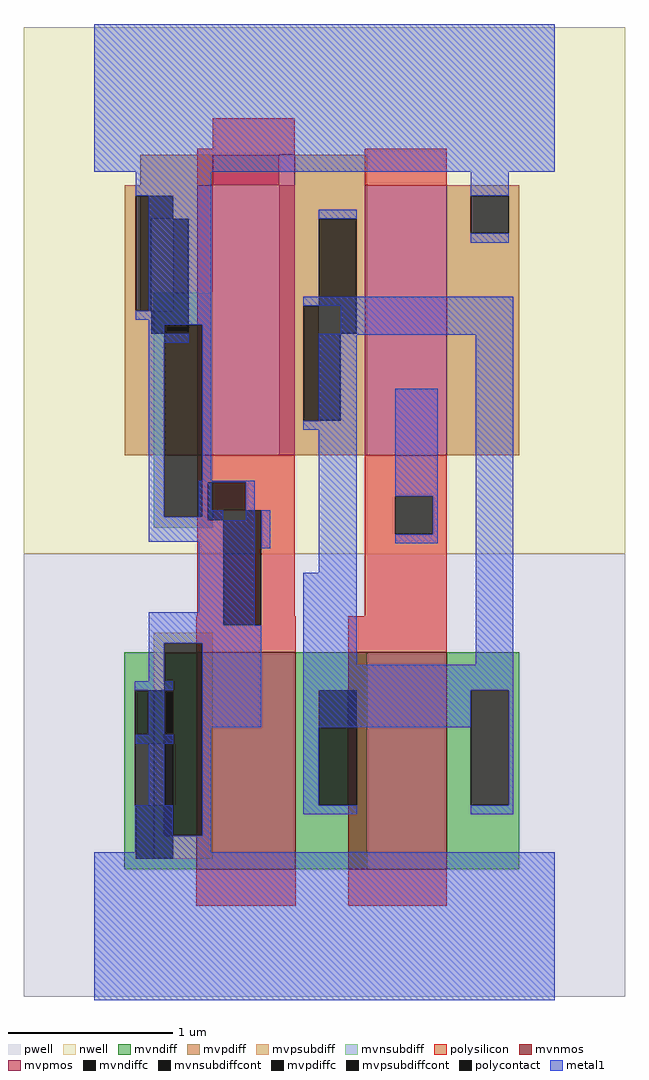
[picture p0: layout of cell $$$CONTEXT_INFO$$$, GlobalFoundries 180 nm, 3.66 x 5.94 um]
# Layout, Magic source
magic
tech gf180mcuD
magscale 1 10
use gf180mcu_fd_sc_mcu9t5v0__filltie  gf180mcu_fd_sc_mcu9t5v0__filltie_0
transform 1 0 0 0 1 0
box -86 -90 310 1098
use gf180mcu_fd_sc_mcu9t5v0__inv_1  gf180mcu_fd_sc_mcu9t5v0__inv_1_0
transform 1 0 0 0 1 0
box -86 -90 534 1098
use gf180mcu_fd_sc_mcu9t5v0__nand2_1  gf180mcu_fd_sc_mcu9t5v0__nand2_1_0
transform 1 0 0 0 1 0
box -86 -90 646 1098
<< end >>

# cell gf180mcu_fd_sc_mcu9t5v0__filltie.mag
magic
tech gf180mcuD
magscale 1 10
<< nwell >>
rect -86 453 310 1094
<< pwell >>
rect -86 -86 310 453
<< mvpsubdiff >>
rect 72 344 144 357
rect 72 110 85 344
rect 131 110 144 344
rect 72 82 144 110
<< mvnsubdiff >>
rect 72 732 144 771
rect 72 498 85 732
rect 131 498 144 732
rect 72 485 144 498
<< mvpsubdiffcont >>
rect 85 110 131 344
<< mvnsubdiffcont >>
rect 85 498 131 732
<< metal1 >>
rect 0 918 224 1098
rect 66 732 142 918
rect 66 498 85 732
rect 131 498 142 732
rect 66 468 142 498
rect 66 344 142 382
rect 66 110 85 344
rect 131 110 142 344
rect 66 90 142 110
rect 0 -90 224 90
<< labels >>
flabel metal1 s 112 -90 112 -90 0 FreeSans 200 0 0 0 VSS
port 1 nsew
flabel metal1 s 112 1098 112 1098 0 FreeSans 200 0 0 0 VDD
port 2 nsew
<< properties >>
string FIXED_BBOX 0 0 224 1008
<< end >>

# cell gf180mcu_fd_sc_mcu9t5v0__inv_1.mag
magic
tech gf180mcuD
magscale 1 10
<< nwell >>
rect -86 453 534 1094
<< pwell >>
rect -86 -86 534 453
<< mvnmos >>
rect 124 69 244 333
<< mvpmos >>
rect 144 573 244 939
<< mvndiff >>
rect 36 287 124 333
rect 36 147 49 287
rect 95 147 124 287
rect 36 69 124 147
rect 244 287 332 333
rect 244 147 273 287
rect 319 147 332 287
rect 244 69 332 147
<< mvpdiff >>
rect 56 861 144 939
rect 56 721 69 861
rect 115 721 144 861
rect 56 573 144 721
rect 244 861 332 939
rect 244 721 273 861
rect 319 721 332 861
rect 244 573 332 721
<< mvndiffc >>
rect 49 147 95 287
rect 273 147 319 287
<< mvpdiffc >>
rect 69 721 115 861
rect 273 721 319 861
<< polysilicon >>
rect 144 939 244 983
rect 144 506 244 573
rect 144 377 157 506
rect 124 366 157 377
rect 203 366 244 506
rect 124 333 244 366
rect 124 25 244 69
<< polycontact >>
rect 157 366 203 506
<< metal1 >>
rect 0 918 448 1098
rect 69 861 115 918
rect 69 710 115 721
rect 273 861 319 872
rect 142 366 157 506
rect 203 460 214 506
rect 273 430 319 721
rect 49 287 95 298
rect 142 242 203 366
rect 254 287 319 430
rect 49 90 95 147
rect 254 147 273 287
rect 254 136 319 147
rect 0 -90 448 90
<< labels >>
flabel metal1 s 168 392 168 392 0 FreeSans 200 0 0 0 I
port 1 nsew
flabel metal1 s 224 1098 224 1098 0 FreeSans 200 0 0 0 VDD
port 2 nsew
flabel metal1 s 224 -90 224 -90 0 FreeSans 200 0 0 0 VSS
port 3 nsew
flabel metal1 s 280 392 280 392 0 FreeSans 200 0 0 0 ZN
port 4 nsew
flabel nwell s 69 784 69 784 0 FreeSans 400 0 0 0 VNW
port 5 nsew
flabel pwell s 68 -17 68 -17 0 FreeSans 400 0 0 0 VPW
port 6 nsew
<< properties >>
string FIXED_BBOX 0 0 448 1008
<< end >>

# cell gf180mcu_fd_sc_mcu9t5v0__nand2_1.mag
magic
tech gf180mcuD
magscale 1 10
<< nwell >>
rect -86 453 646 1094
<< pwell >>
rect -86 -86 646 453
<< mvnmos >>
rect 125 69 245 333
rect 309 69 429 333
<< mvpmos >>
rect 125 573 225 902
rect 329 573 429 902
<< mvndiff >>
rect 37 222 125 333
rect 37 82 50 222
rect 96 82 125 222
rect 37 69 125 82
rect 245 69 309 333
rect 429 287 517 333
rect 429 147 458 287
rect 504 147 517 287
rect 429 69 517 147
<< mvpdiff >>
rect 37 889 125 902
rect 37 749 50 889
rect 96 749 125 889
rect 37 573 125 749
rect 225 755 329 902
rect 225 615 254 755
rect 300 615 329 755
rect 225 573 329 615
rect 429 889 517 902
rect 429 843 458 889
rect 504 843 517 889
rect 429 573 517 843
<< mvndiffc >>
rect 50 82 96 222
rect 458 147 504 287
<< mvpdiffc >>
rect 50 749 96 889
rect 254 615 300 755
rect 458 843 504 889
<< polysilicon >>
rect 125 902 225 946
rect 329 902 429 946
rect 125 540 225 573
rect 125 494 138 540
rect 184 494 225 540
rect 125 377 225 494
rect 329 523 429 573
rect 329 477 366 523
rect 412 477 429 523
rect 329 377 429 477
rect 125 333 245 377
rect 309 333 429 377
rect 125 25 245 69
rect 309 25 429 69
<< polycontact >>
rect 138 494 184 540
rect 366 477 412 523
<< metal1 >>
rect 0 918 560 1098
rect 50 889 96 918
rect 458 889 504 918
rect 458 832 504 843
rect 50 738 96 749
rect 254 755 510 766
rect 300 720 510 755
rect 300 615 306 720
rect 254 604 306 615
rect 127 540 195 542
rect 127 494 138 540
rect 184 494 195 540
rect 127 354 195 494
rect 366 523 418 654
rect 412 477 418 523
rect 366 466 418 477
rect 464 318 510 720
rect 254 287 510 318
rect 254 242 458 287
rect 50 222 96 233
rect 0 82 50 90
rect 504 147 510 287
rect 458 136 510 147
rect 96 82 560 90
rect 0 -90 560 82
<< labels >>
flabel metal1 s 392 504 392 504 0 FreeSans 200 0 0 0 A1
port 1 nsew
flabel metal1 s 168 392 168 392 0 FreeSans 200 0 0 0 A2
port 2 nsew
flabel metal1 s 280 1098 280 1098 0 FreeSans 200 0 0 0 VDD
port 3 nsew
flabel metal1 s 280 -90 280 -90 0 FreeSans 200 0 0 0 VSS
port 4 nsew
flabel metal1 s 392 280 392 280 0 FreeSans 200 0 0 0 ZN
port 5 nsew
flabel nwell s 69 784 69 784 0 FreeSans 400 0 0 0 VNW
port 6 nsew
flabel pwell s 68 -17 68 -17 0 FreeSans 400 0 0 0 VPW
port 7 nsew
<< properties >>
string FIXED_BBOX 0 0 560 1008
<< end >>
